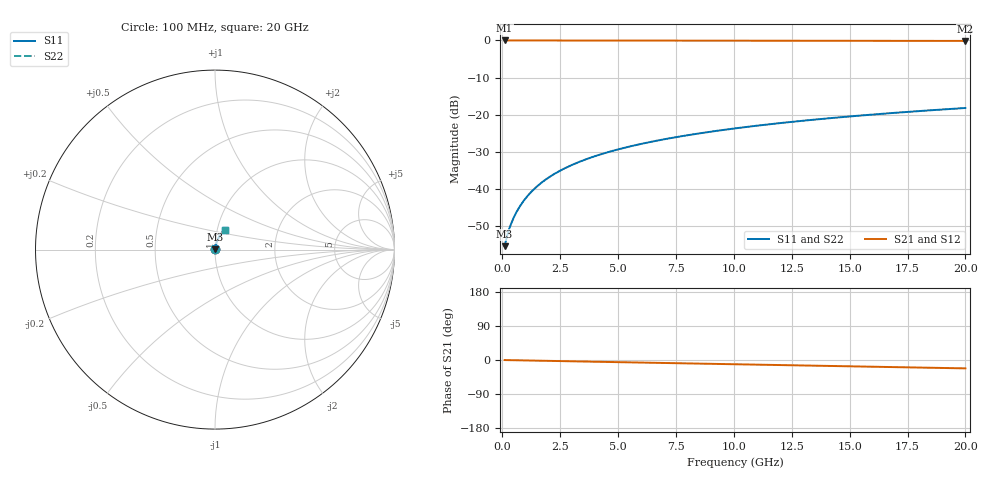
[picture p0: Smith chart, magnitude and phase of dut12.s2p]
! Touchstone file exported from HFSS 2026.1.0
!  File:  C:/ffzhzh/LocalFiles/Ansys_Project_Files/temp_test_BSMRDL_12_1782907403_46784.aedt
!  Generated:  08:04:32 PM Jul  1, 2026
!  Design:  BSMRDL
!  Project:  temp_test_BSMRDL_12_1782907403_46784
! Variables:
!  h_bsmrdl = 4.54um
!  h_ox = 20um
!  h_rdl = 5um
!  h_sub = 80um
!  h_tmrdl = 5um
!  h_tsv = 80um
!  h_via = 3um
!  l_bsmrdl = 357.49um
!  l_sub = 757.49um
!  l_tmrdl = 200um
!  m_sub = 200um
!  pitch = 33.39um
!  r_tsv = 6um
!  s_tmrdl = 10um
!  w_bsmrdl = 22.01um
!  w_sub = 500um
!  w_tmrdl = 12um
!  x_tsv_center1 = 206um
!  x_tsv_center2 = 585.5um
!  x_tsv_center3 = 797.5um
!  x_tsv_center4 = 1177um
!  x_tsv_center5 = 1389um
!  x_tsv_center6 = 1768.5um
# GHz S MA R 50.000000
! Terminal data exported
! Port[1] = BSM_RDL1_1_T1
! Port[2] = BSM_RDL1_1_T2
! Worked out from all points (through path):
!   200 points, 100 MHz to 20 GHz, reference 50 ohm
!   highest |S21| = -0.01 dB at 100 MHz (marker M1); lowest = -0.1 dB at 20 GHz (marker M2)
!   group delay of S21, straight-line fit = 3.06 ps
!   lowest |S11| = -55.3 dB at 100 MHz (marker M3), VSWR 1.00, Z = 50.1 + j0.089 ohm
!   |S11| at or under -10 dB: start of sweep to end of sweep
!   |S22| runs from -55.3 to -18.2 dB; largest |S21 - S12| = 3.3e-15
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0.1  0.001715 31.2  0.9985 -0.1  0.9985 -0.1  0.001715 31.2
! Gamma 0 0 0 0
! Port Impedance 50 0 50 0
0.2  0.002317 46.1  0.9984 -0.2  0.9984 -0.2  0.002317 46.1
0.3  0.002938 54.1  0.9983 -0.4  0.9983 -0.4  0.002939 54.1
0.4  0.003559 59.4  0.9982 -0.5  0.9982 -0.5  0.003559 59.4
0.5  0.004188 63.4  0.9981 -0.6  0.9981 -0.6  0.004188 63.4
0.6  0.004829 66.4  0.9981 -0.7  0.9981 -0.7  0.00483 66.4
0.8  0.006145 70.6  0.998 -0.9  0.998 -0.9  0.006145 70.6
1  0.007489 73.4  0.9979 -1.2  0.9979 -1.2  0.007489 73.4
1.2  0.00885 75.2  0.9979 -1.4  0.9979 -1.4  0.00885 75.2
1.4  0.01022 76.4  0.9978 -1.6  0.9978 -1.6  0.01022 76.4
1.7  0.01228 77.6  0.9977 -2.0  0.9977 -2.0  0.01228 77.6
2.2  0.01571 78.6  0.9974 -2.5  0.9974 -2.5  0.01571 78.6
2.8  0.01978 78.9  0.9971 -3.2  0.9971 -3.2  0.01978 78.9
3.5  0.02447 78.8  0.9966 -4.0  0.9966 -4.0  0.02447 78.8
4.2  0.02908 78.5  0.9962 -4.8  0.9962 -4.8  0.02908 78.5
5  0.03427 77.9  0.9956 -5.7  0.9956 -5.7  0.03427 77.9
6.8  0.04569 76.5  0.9943 -7.7  0.9943 -7.7  0.04569 76.5
8.3  0.05499 75.2  0.9933 -9.3  0.9933 -9.3  0.05499 75.2
10.1  0.06598 73.6  0.992 -11.3  0.992 -11.3  0.06598 73.6
13.4  0.08569 70.5  0.9895 -14.9  0.9895 -14.9  0.0857 70.5
16.7  0.1049 67.4  0.9869 -18.5  0.9869 -18.5  0.1049 67.4
20  0.1235 64.1  0.9841 -22.1  0.9841 -22.1  0.1235 64.1
